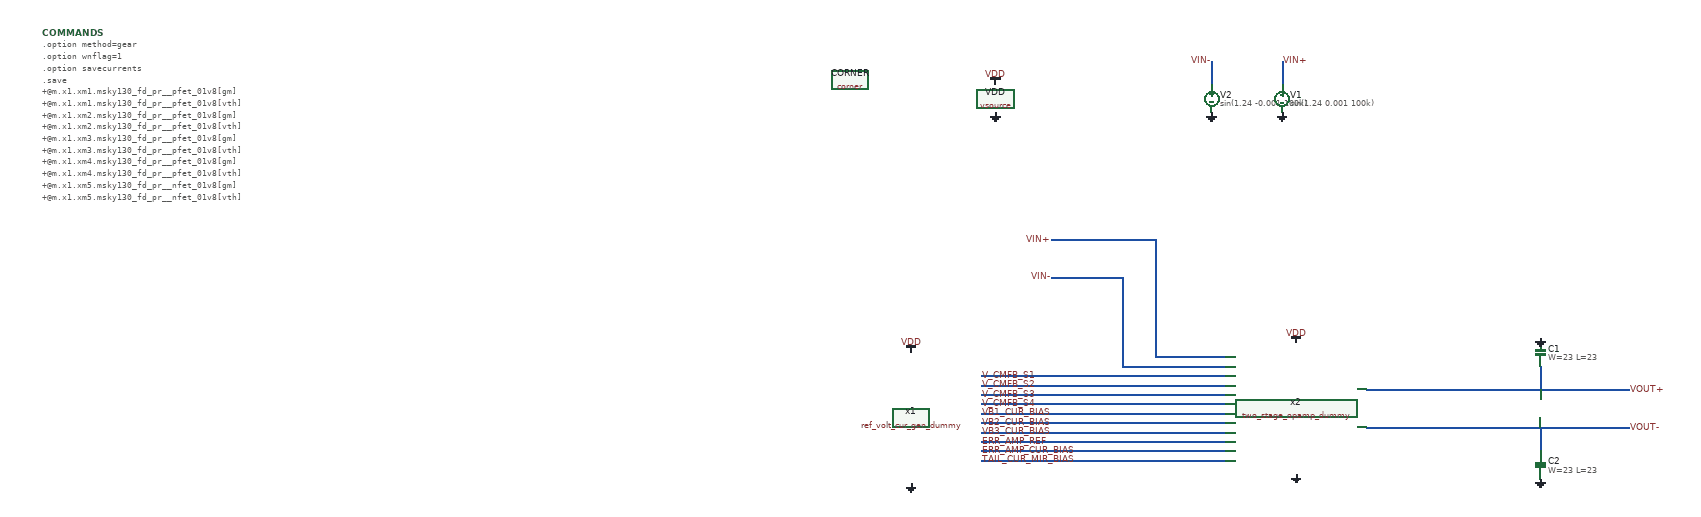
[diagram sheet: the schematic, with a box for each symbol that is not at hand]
v {xschem version=3.4.6 file_version=1.2}
G {}
K {}
V {}
S {}
E {}
B 2 6040 -2000 6760 -1510 {flags=graph

y2=1.8
ypos1=0
ypos2=2
divy=5
subdivy=4
unity=1
x1=8.5143355e-06
x2=2.0802335e-05
divx=5
subdivx=4
xlabmag=1.0
ylabmag=1.0


dataset=0
unitx=1
logx=0
logy=0











linewidth_mult=1
























y1=-1.7e-11







color="6 7"
node="vout+
vout-"}
B 2 5230 -2000 5950 -1510 {flags=graph

y2=0.97
ypos1=0
ypos2=2
divy=5
subdivy=4
unity=1
x1=8.5143355e-06
x2=2.0802335e-05
divx=5
subdivx=4
xlabmag=1.0
ylabmag=1.0


dataset=0
unitx=1
logx=0
logy=0











linewidth_mult=2
























y1=0.82








color="6 7 11"
node="x2.x
x2.y
vdd"}
B 2 5230 -1450 5950 -960 {flags=graph

y2=0.15
ypos1=0
ypos2=2
divy=5
subdivy=4
unity=1
x1=8.5143355e-06
x2=2.0802335e-05
divx=5
subdivx=4
xlabmag=1.0
ylabmag=1.0


dataset=0
unitx=1
logx=0
logy=0











linewidth_mult=2
























y1=-0.15








color=6
node="\\"x2.x  x2.y -\\""}
B 2 6040 -1450 6760 -960 {flags=graph

y2=0.97
ypos1=0
ypos2=2
divy=5
subdivy=4
unity=1
x1=8.5143355e-06
x2=2.0802335e-05
divx=5
subdivx=4
xlabmag=1.0
ylabmag=1.0


dataset=0
unitx=1
logx=0
logy=0











linewidth_mult=2
























y1=-0.97







color=6
node="\\"vout+ vout- -\\""}
B 2 4420 -2000 5140 -1510 {flags=graph

y2=1.2472079
ypos1=0
ypos2=2
divy=5
subdivy=4
unity=1
x1=8.5143355e-06
x2=2.0802335e-05
divx=5
subdivx=4
xlabmag=1.0
ylabmag=1.0


dataset=0
unitx=1
logx=0
logy=0











linewidth_mult=2
























y1=1.2337861









color="6 7"
node="vin+
vin-"}
B 2 3600 -1450 4320 -960 {flags=graph

y2=1.5e-05
ypos1=0
ypos2=2
divy=5
subdivy=4
unity=1
x1=8.5143355e-06
x2=2.0802335e-05
divx=5
subdivx=4
xlabmag=1.0
ylabmag=1.0


dataset=0
unitx=1
logx=0
logy=0











linewidth_mult=6
























y1=0









color=6
node=i(@m.x1.xm8.msky130_fd_pr__pfet_01v8[id])}
B 2 6860 -2000 7580 -1510 {flags=graph

y2=0.31
ypos1=0
ypos2=2
divy=5
subdivy=8
unity=1
x1=8.5143355e-06
x2=2.0802335e-05
divx=5
subdivx=8
xlabmag=1.0
ylabmag=1.0


dataset=0
unitx=1
logx=1
logy=1











linewidth_mult=2
























y1=0.031








color=6
node="\\"x2.x x2.y +\\""}
B 2 6860 -1450 7580 -960 {flags=graph

y2=10
ypos1=0
ypos2=2
divy=5
subdivy=4
unity=1
x1=8.5143355e-06
x2=2.0802335e-05
divx=5
subdivx=8
xlabmag=1.0
ylabmag=1.0


dataset=0
unitx=1
logx=1
logy=0











linewidth_mult=2
























y1=-180








color=6
node="\\"ph(x2.x) ph(x2.y) + 180 -\\""}
B 2 7680 -2000 8400 -1510 {flags=graph

y2=0.026
ypos1=0
ypos2=2
divy=5
subdivy=8
unity=1
x1=8.5143355e-06
x2=2.0802335e-05
divx=5
subdivx=8
xlabmag=1.0
ylabmag=1.0


dataset=0
unitx=1
logx=1
logy=1











linewidth_mult=2
























y1=-2.6










color=6
node="\\"vout+ vout- + \\""}
B 2 7680 -1450 8400 -960 {flags=graph

y2=-7.6e-05
ypos1=0
ypos2=2
divy=5
subdivy=4
unity=1
x1=8.5143355e-06
x2=2.0802335e-05
divx=5
subdivx=8
xlabmag=1.0
ylabmag=1.0


dataset=0
unitx=1
logx=1
logy=0











linewidth_mult=2
























y1=-180









color=6
node="\\"ph(vout+) ph(vout-) + 180 - 2 /\\""}
B 2 3600 -900 4320 -410 {flags=graph

y2=2.8e-05
ypos1=0
ypos2=2
divy=5
subdivy=4
unity=1
x1=8.5143355e-06
x2=2.0802335e-05
divx=5
subdivx=4
xlabmag=1.0
ylabmag=1.0


dataset=0
unitx=1
logx=0
logy=0











linewidth_mult=6
























y1=4.5e-16










color=6
node=i(@m.x2.xm19.msky130_fd_pr__nfet_01v8[id])}
B 2 8500 -1450 9220 -960 {flags=graph

y2=45
ypos1=0
ypos2=2
divy=5
subdivy=4
unity=1
x1=8.5143355e-06
x2=2.0802335e-05
divx=5
subdivx=8
xlabmag=1.0
ylabmag=1.0


dataset=0
unitx=1
logx=1
logy=0











linewidth_mult=2
























y1=-65









color=6
node=\\"ph(vout+)\\"}
B 2 7680 -2560 8400 -2070 {flags=graph

y2=3.1
ypos1=0
ypos2=2
divy=5
subdivy=8
unity=1
x1=8.5143355e-06
x2=2.0802335e-05
divx=5
subdivx=8
xlabmag=1.0
ylabmag=1.0


dataset=0
unitx=1
logx=1
logy=1











linewidth_mult=2
























y1=-18










color=6
node="\\"vout+ vout- + frequency / \\""}
B 2 4420 -1450 5140 -960 {flags=graph

y2=0.002
ypos1=0
ypos2=2
divy=5
subdivy=4
unity=1
x1=8.5143355e-06
x2=2.0802335e-05
divx=5
subdivx=4
xlabmag=1.0
ylabmag=1.0


dataset=0
unitx=1
logx=0
logy=0











linewidth_mult=2
























y1=-0.002









color=6
node="\\"vin+ vin- - \\""}
B 2 8500 -2000 9220 -1510 {flags=graph

y2=2.7
ypos1=0
ypos2=2
divy=5
subdivy=8
unity=1
x1=8.5143355e-06
x2=2.0802335e-05
divx=5
subdivx=8
xlabmag=1.0
ylabmag=1.0


dataset=0
unitx=1
logx=1
logy=1











linewidth_mult=2
























y1=-0.027










color=6
node="\\"vdd vout+ vout- + /\\""}
B 2 6040 -2560 6760 -2070 {flags=graph

y2=0.0013
ypos1=0
ypos2=2
divy=5
subdivy=4
unity=1
x1=8.5143355e-06
x2=2.0802335e-05
divx=5
subdivx=4
xlabmag=1.0
ylabmag=1.0


dataset=0
unitx=1
logx=0
logy=0











linewidth_mult=1
























y1=0








color="6 7"
node="\\"i(@m.x2.xm15.msky130_fd_pr__nfet_01v8[id]) i(@m.x2.xm41.msky130_fd_pr__nfet_01v8[id]) + \\"
i(@m.x2.xm41.msky130_fd_pr__nfet_01v8[id])"}
B 2 6040 -3110 6760 -2620 {flags=graph

y2=1.4
ypos1=0
ypos2=2
divy=5
subdivy=4
unity=1
x1=8.5143355e-06
x2=2.0802335e-05
divx=5
subdivx=4
xlabmag=1.0
ylabmag=1.0


dataset=0
unitx=1
logx=0
logy=0











linewidth_mult=1
























y1=0.012







color=6
node="\\"vout+ vin+ /\\""}
B 2 6040 -3660 6760 -3170 {flags=graph

y2=260
ypos1=0
ypos2=2
divy=5
subdivy=4
unity=1
x1=8.5143355e-06
x2=2.0802335e-05
divx=5
subdivx=4
xlabmag=1.0
ylabmag=1.0


dataset=0
unitx=1
logx=0
logy=0











linewidth_mult=1
























y1=0







color=6
node="\\"vout+ deriv()\\""}
N 3170 -4110 3170 -4060 {lab=VIN-}
N 3320 -4110 3320 -4060 {lab=VIN+}
N 3500 -3330 4060 -3330 {lab=VOUT-}
N 3500 -3410 4060 -3410 {lab=VOUT+}
N 3870 -3460 3870 -3410 {lab=VOUT+}
N 3870 -3330 3870 -3280 {lab=VOUT-}
N 2680 -3260 3200 -3260 {lab=TAIL_CUR_MIR_BIAS}
N 2680 -3280 3200 -3280 {lab=ERR_AMP_CUR_BIAS}
N 2680 -3300 3200 -3300 {lab=ERR_AMP_REF}
N 2680 -3320 3200 -3320 {lab=VB3_CUR_BIAS}
N 2680 -3340 3200 -3340 {lab=VB2_CUR_BIAS}
N 2680 -3360 3200 -3360 {lab=VB1_CUR_BIAS}
N 2680 -3380 3200 -3380 {lab=V_CMFB_S4}
N 2680 -3400 3200 -3400 {lab=V_CMFB_S3}
N 2680 -3420 3200 -3420 {lab=V_CMFB_S2}
N 2680 -3440 3200 -3440 {lab=V_CMFB_S1}
N 2980 -3460 3200 -3460 {lab=#net1}
N 2980 -3650 2980 -3460 {lab=#net1}
N 2830 -3650 2980 -3650 {lab=#net1}
N 3050 -3480 3200 -3480 {lab=VIN+}
N 3050 -3730 3050 -3480 {lab=VIN+}
N 2830 -3730 3050 -3730 {lab=VIN+}
C {devices/vsource.sym} 2710 -4030 0 0 {name=VDD value="pwl(0 0 3us 0 4us 1.8)"  savecurrent=false
* "1.8 AC 1"  "sin(1.8 0.001 10k)" 1.8}
C {devices/gnd.sym} 2710 -4000 0 0 {name=l3 lab=GND}
C {devices/vdd.sym} 2710 -4060 0 0 {name=l4 lab=VDD}
C {sky130_fd_pr/corner.sym} 2400 -4070 0 0 {name=CORNER only_toplevel=false corner=tt}
C {simulator_commands_shown.sym} 680 -4170 0 0 {name=COMMANDS
simulator=ngspice
only_toplevel=false 
value="

.option method=gear
.option wnflag=1
.option savecurrents

.save
+@m.x1.xm1.msky130_fd_pr__pfet_01v8[gm]
+@m.x1.xm1.msky130_fd_pr__pfet_01v8[vth]
+@m.x1.xm2.msky130_fd_pr__pfet_01v8[gm]
+@m.x1.xm2.msky130_fd_pr__pfet_01v8[vth]
+@m.x1.xm3.msky130_fd_pr__pfet_01v8[gm]
+@m.x1.xm3.msky130_fd_pr__pfet_01v8[vth]
+@m.x1.xm4.msky130_fd_pr__pfet_01v8[gm]
+@m.x1.xm4.msky130_fd_pr__pfet_01v8[vth]
+@m.x1.xm5.msky130_fd_pr__nfet_01v8[gm]
+@m.x1.xm5.msky130_fd_pr__nfet_01v8[vth]
+@m.x1.xm6.msky130_fd_pr__pfet_01v8[gm]
+@m.x1.xm6.msky130_fd_pr__pfet_01v8[vth]
+@m.x1.xm7.msky130_fd_pr__nfet_01v8[gm]
+@m.x1.xm7.msky130_fd_pr__nfet_01v8[vth]
+@m.x1.xm8.msky130_fd_pr__pfet_01v8[gm]
+@m.x1.xm8.msky130_fd_pr__pfet_01v8[vth]
+@m.x2.xm2.msky130_fd_pr__nfet_01v8[gm]
+@m.x2.xm2.msky130_fd_pr__nfet_01v8[vth]
+@m.x2.xm3.msky130_fd_pr__nfet_01v8[gm]
+@m.x2.xm3.msky130_fd_pr__nfet_01v8[vth]
+@m.x2.xm7.msky130_fd_pr__pfet_01v8[gm]
+@m.x2.xm7.msky130_fd_pr__pfet_01v8[vth]
+@m.x1.x1.xm1.msky130_fd_pr__nfet_01v8[gm]
+@m.x1.x1.xm2.msky130_fd_pr__nfet_01v8[gm]
+@m.x1.x1.xm3.msky130_fd_pr__nfet_01v8[gm]
+@m.x1.x1.xm4.msky130_fd_pr__nfet_01v8[gm]
+@m.x1.x1.xm5.msky130_fd_pr__pfet_01v8[gm]
+@m.x1.x1.xm6.msky130_fd_pr__nfet_01v8[gm]
+@m.x1.x1.xm7.msky130_fd_pr__pfet_01v8[gm]
+@m.x1.x2.xm1.msky130_fd_pr__nfet_01v8[gm]
+@m.x1.x2.xm2.msky130_fd_pr__nfet_01v8[gm]
+@m.x1.x2.xm3.msky130_fd_pr__nfet_01v8[gm]
+@m.x1.x2.xm4.msky130_fd_pr__nfet_01v8[gm]
+@m.x1.x2.xm5.msky130_fd_pr__pfet_01v8[gm]
+@m.x1.x2.xm6.msky130_fd_pr__nfet_01v8[gm]
+@m.x1.x2.xm7.msky130_fd_pr__pfet_01v8[gm]
+@m.x2.xm39.msky130_fd_pr__pfet_01v8[gm]
+@m.x2.xm39.msky130_fd_pr__pfet_01v8[vth]
+@m.x2.xm40.msky130_fd_pr__pfet_01v8[gm]
+@m.x2.xm40.msky130_fd_pr__pfet_01v8[vth]

* .ic v(v_top) = 1.8

.control

  * let runs=3
  * let run=1

  * dowhile run <= runs
    * save v(vout+) v(vout-) v(vin+) v(vin-) v(v_err_amp_ref) v(x2.x) v(x2.y) v(x2.vb1) v(x2.vb2) v(x2.vb3) v(x2.v_tot)
    save all
    remzerovec
    set appendwrite
    * dc temp -40 120 10 VDD 0 4.0 0.2
    * dc VDD 0 2.0 0.02 temp -40 120 40
    * dc V5 0 0.01 0.0001
    tran 2n 30u
    * tran 1p 3n
    * tran 0.1ns 30us
    * ac dec 40 1 10T
    write tb_opamp_full_6.raw
    * write tb_opamp_full_6_mc.raw
    * write tb_opamp_full_6_tt_mm.raw
    * write tb_opamp_full_6_AC.raw
    * reset
    * let run = run + 1
  * end
.endc

"}
C {lab_pin.sym} 4060 -3410 2 0 {name=p6 lab=VOUT+}
C {lab_pin.sym} 4060 -3330 0 1 {name=p7 lab=VOUT-}
C {lab_pin.sym} 2830 -3730 2 1 {name=p10 lab=VIN+}
C {lab_pin.sym} 2830 -3650 0 0 {name=p11 lab=VIN-}
C {devices/gnd.sym} 2530 -3210 0 0 {name=l2 lab=GND}
C {devices/vsource.sym} 3170 -4030 0 1 {name=V2 value="sin(1.24 -0.001 100k)" savecurrent=false
* "1.24 AC -1"
* "sin(1.24 -0.001 1Meg)"
* "sin(0.2 -0.001 1Meg)" 
* "pulse(1.24 1.04 0ns 2ns 2ns 48ns 100ns)"
* "pulse(1.24 1.23 0ns 2ns 2ns 48ns 100ns)" "pulse(1.24 1.23 0ns 0.8ns 0.8ns 19.2ns 40ns)"}
C {devices/vsource.sym} 3320 -4030 0 0 {name=V1 value="sin(1.24 0.001 100k)" savecurrent=false
* "1.24 AC 1"
* "sin(1.24 0.001 1Meg)"  
* "sin(0.2 0.001 1Meg)" "pulse(1.24 1.44 0ns 2ns 2ns 48ns 100ns)"
* 1.24
*  "pulse(1.24 1.34 0ns 2ns 2ns 48ns 100ns)" "pulse(1.24 1.25 0ns 0.8ns 0.8ns 19.2ns 40ns)"}
C {devices/gnd.sym} 3170 -4000 0 0 {name=V3 value="pulse(1.241 1.239 0ns 10ns 10ns 240ns 500ns)" savecurrent=false
* "1.24 AC -1"
* "sin(1.24 -0.001 100k)"
* "sin(0.2 -0.001 1Meg)" "sin(1.24 -0.001 1Meg)"
* "pwl(0 1.24 3us 1.24 3.01us 1.239)"}
C {devices/gnd.sym} 3320 -4000 0 0 {name=V4 value="pulse(1.241 1.239 0ns 10ns 10ns 240ns 500ns)" savecurrent=false
* "1.24 AC -1"
* "sin(1.24 -0.001 100k)"
* "sin(0.2 -0.001 1Meg)" "sin(1.24 -0.001 1Meg)"
* "pwl(0 1.24 3us 1.24 3.01us 1.239)"}
C {lab_pin.sym} 3320 -4110 0 1 {name=p2 lab=VIN+}
C {lab_pin.sym} 3170 -4110 0 0 {name=p3 lab=VIN-}
C {sky130_fd_pr/cap_mim_m3_1.sym} 3870 -3490 2 1 {name=C1 model=cap_mim_m3_1 W=23 L=23 MF=1 spiceprefix=X}
C {devices/gnd.sym} 3870 -3520 2 1 {name=l13 lab=GND}
C {sky130_fd_pr/cap_mim_m3_1.sym} 3870 -3250 0 0 {name=C2 model=cap_mim_m3_1 W=23 L=23 MF=1 spiceprefix=X}
C {devices/gnd.sym} 3870 -3220 0 0 {name=l14 lab=GND}
C {devices/vdd.sym} 2530 -3490 0 0 {name=l1 lab=VDD}
C {ref_volt_cur_gen_dummy.sym} 2530 -3350 0 0 {name=x1}
C {two_stage_opamp_dummy.sym} 3350 -3370 0 0 {name=x2}
C {lab_pin.sym} 2680 -3300 0 1 {name=p5 lab=ERR_AMP_REF}
C {lab_pin.sym} 2680 -3400 0 1 {name=p8 lab=V_CMFB_S3}
C {lab_pin.sym} 2680 -3360 0 1 {name=p12 lab=VB1_CUR_BIAS}
C {lab_pin.sym} 2680 -3260 0 1 {name=p13 lab=TAIL_CUR_MIR_BIAS}
C {lab_pin.sym} 2680 -3440 0 1 {name=p14 lab=V_CMFB_S1}
C {lab_pin.sym} 2680 -3280 0 1 {name=p15 lab=ERR_AMP_CUR_BIAS}
C {lab_pin.sym} 2680 -3320 0 1 {name=p16 lab=VB3_CUR_BIAS}
C {lab_pin.sym} 2680 -3380 0 1 {name=p17 lab=V_CMFB_S4}
C {lab_pin.sym} 2680 -3420 0 1 {name=p18 lab=V_CMFB_S2}
C {lab_pin.sym} 2680 -3340 0 1 {name=p19 lab=VB2_CUR_BIAS}
C {devices/gnd.sym} 3350 -3230 0 0 {name=l7 lab=GND}
C {devices/vdd.sym} 3350 -3510 0 0 {name=l8 lab=VDD}
